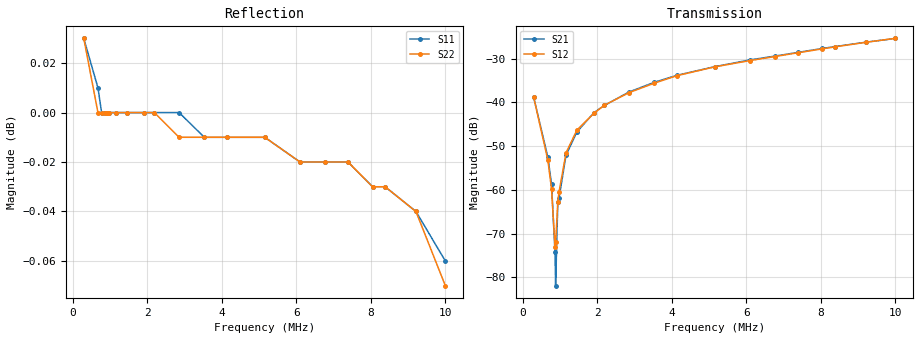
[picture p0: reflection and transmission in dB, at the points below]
!s-Parameter Generated by FASTRON Sdn. Bhd.
!FASTRON P/N : 1812AFTC-412X
!Keysight Technologies: E5071C_MY46733604_B.14.02
!Date: Wed Mar 18 14:02:16 2026
!Version  :Rev00  Wed Mar 18 14:02:16 2026
!Data & Calibration Information:
!Freq  S11:SOLT2(ON)  S21:SOLT2(ON)  S12:SOLT2(ON)  S22:SOLT2(ON)
!PortZ  Port1:50+j0  Port2:50+j0
!When reading reference impedance value at option line is always used.
! Remarks : This data is being provided solely for informational purposes.
# Hz S dB R 50
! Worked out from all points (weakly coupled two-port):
!   1601 points, 300 kHz to 10 MHz, reference 50 ohm
!   highest |S21| = -25.38 dB at 10 MHz (marker M1); lowest = -81.9 dB at 888.5 kHz (marker M2)
!   lowest |S11| = -0.1 dB at 10 MHz (marker M3), VSWR 268.61, Z = 3.27 - j204 ohm
!   |S11| at or under -10 dB: nowhere
!   |S22| runs from -0.1 to 0.0 dB; largest |S21 - S12| = 0.00071
!   S11 on the Smith chart (normalised r, x): 300 kHz: -0, +11; 2.195 MHz: 0.00, +1.35; 4.144 MHz: 0.00, +0.39; 6.102 MHz: 0.00, -0.20; 8.047 MHz: 0.00, -0.96; 10 MHz: 0.07, -4.07
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300000  0.03 10.4  -38.86 -87.3  -38.83 -88.2  0.03 -10.7
680434  0.01 22.8  -52.53 -95.7  -53.23 -88.0  0.00 -25.0
778555  0.00 26.0  -58.67 -77.9  -59.77 -82.4  0.00 -28.6
872380  0.00 29.1  -74.32 49.5  -73.06 14.6  0.00 -32.1
888495  0.00 29.7  -81.93 -19.9  -72.05 -11.0  -0.00 -32.7
946913  0.00 31.6  -62.82 76.8  -62.90 77.5  0.00 -34.9
979144  0.00 32.7  -61.89 61.1  -60.51 80.2  0.00 -36.1
1168378  0.00 39.0  -52.09 87.8  -51.54 85.5  0.00 -43.1
1456578  0.00 48.5  -46.80 86.7  -46.37 84.8  -0.00 -53.7
1917564  -0.00 63.8  -42.34 83.9  -42.49 84.7  -0.00 -70.8
2195107  -0.00 73.1  -40.71 84.8  -40.66 84.4  -0.00 -81.1
2856713  -0.00 95.1  -37.63 83.0  -37.78 82.8  -0.01 -105.5
3534704  -0.01 117.6  -35.41 81.3  -35.61 81.5  -0.01 -130.6
4143721  -0.01 137.8  -33.81 80.2  -33.89 79.6  -0.01 -153.1
5155786  -0.01 171.5  -31.84 78.1  -31.88 78.2  -0.01 169.5
6101602  -0.02 -157.0  -30.29 74.8  -30.44 74.7  -0.02 134.5
6770355  -0.02 -134.8  -29.42 74.5  -29.52 74.4  -0.02 109.8
7390266  -0.02 -114.2  -28.57 73.4  -28.65 73.2  -0.02 86.9
8047393  -0.03 -92.4  -27.67 71.7  -27.75 72.0  -0.03 62.6
8385344  -0.03 -81.2  -27.23 70.8  -27.30 70.9  -0.03 50.0
9211447  -0.04 -53.7  -26.24 68.2  -26.26 68.1  -0.04 19.4
1e7  -0.06 -27.6  -25.38 64.9  -25.36 64.9  -0.07 -9.8
